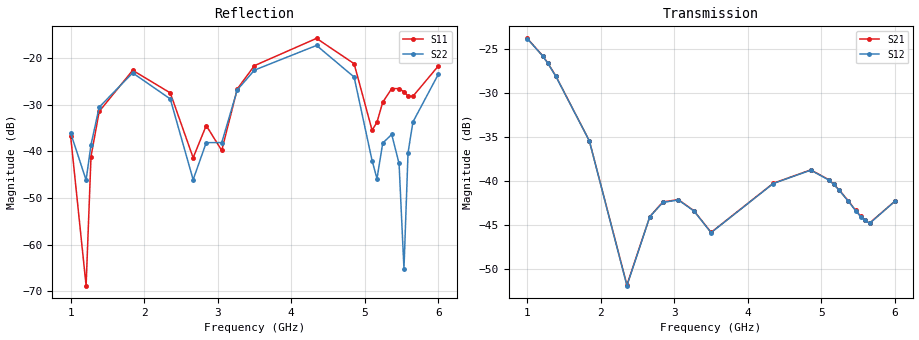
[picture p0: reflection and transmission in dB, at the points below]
!Agilent Technologies,E8364B,MY43040528,A.07.50.67
!Agilent E8364B: A.07.50.67
!Date: Sunday, March 01, 2026 22:56:52
!Correction: S11(Full 2 Port(1,2))
!S21(Full 2 Port(1,2))
!S12(Full 2 Port(1,2))
!S22(Full 2 Port(1,2))
!S2P File: Measurements: S11, S21, S12, S22:
# Hz S  dB  R 50
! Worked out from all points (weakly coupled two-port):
!   451 points, 1 GHz to 6 GHz, reference 50 ohm
!   highest |S21| = -23.84 dB at 1 GHz (marker M1); lowest = -51.8 dB at 2.356 GHz (marker M2)
!   lowest |S11| = -68.8 dB at 1.211 GHz (marker M3), VSWR 1.00, Z = 50 - j0.00832 ohm
!   |S11| at or under -10 dB: start of sweep to end of sweep
!   |S22| runs from -65.2 to -17.2 dB; largest |S21 - S12| = 0.00026
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1e9  -36.60 16.5  -23.84 155.1  -23.87 155.1  -36.01 -42.1
1.211111e9  -68.76 -166.8  -25.82 34.8  -25.85 34.9  -46.13 -154.7
1.277778e9  -41.10 -162.2  -26.61 -2.8  -26.64 -2.8  -38.55 168.7
1.388889e9  -31.42 176.4  -28.11 -64.7  -28.14 -64.6  -30.52 124.2
1.844444e9  -22.62 76.7  -35.44 51.8  -35.46 51.8  -23.17 -5.2
2.355556e9  -27.46 0.1  -51.78 -148.0  -51.86 -148.1  -28.75 -122.6
2.666667e9  -41.35 41.8  -44.03 104.6  -44.05 104.7  -46.05 37.7
2.844444e9  -34.45 49.6  -42.37 13.4  -42.42 13.4  -38.11 -51.2
3.055556e9  -39.78 80.6  -42.11 -97.4  -42.15 -97.3  -38.10 -20.4
3.266667e9  -26.60 102.1  -43.37 154.5  -43.40 154.6  -26.81 -48.3
3.5e9  -21.62 63.6  -45.82 47.2  -45.85 47.3  -22.58 -104.7
4.344444e9  -15.77 -41.6  -40.26 25.3  -40.29 25.3  -17.28 103.4
4.855556e9  -21.20 -129.8  -38.74 99.2  -38.77 99.1  -24.06 -21.0
5.1e9  -35.46 -120.4  -39.85 -45.4  -39.89 -45.5  -41.97 -115.3
5.166667e9  -33.71 -72.6  -40.36 -85.8  -40.39 -85.7  -45.83 111.4
5.244444e9  -29.46 -67.0  -41.04 -133.4  -41.07 -133.5  -38.21 63.3
5.366667e9  -26.53 -78.8  -42.26 149.1  -42.30 149.1  -36.36 19.7
5.466667e9  -26.52 -90.0  -43.33 82.5  -43.37 82.5  -42.57 -16.7
5.533333e9  -27.23 -91.6  -43.99 36.0  -44.03 36.1  -65.16 63.0
5.588889e9  -28.09 -89.5  -44.44 -3.8  -44.46 -3.9  -40.25 119.6
5.655556e9  -28.18 -82.3  -44.76 -52.9  -44.80 -52.9  -33.67 103.1
6e9  -21.70 -82.0  -42.28 61.9  -42.29 61.8  -23.48 3.6
